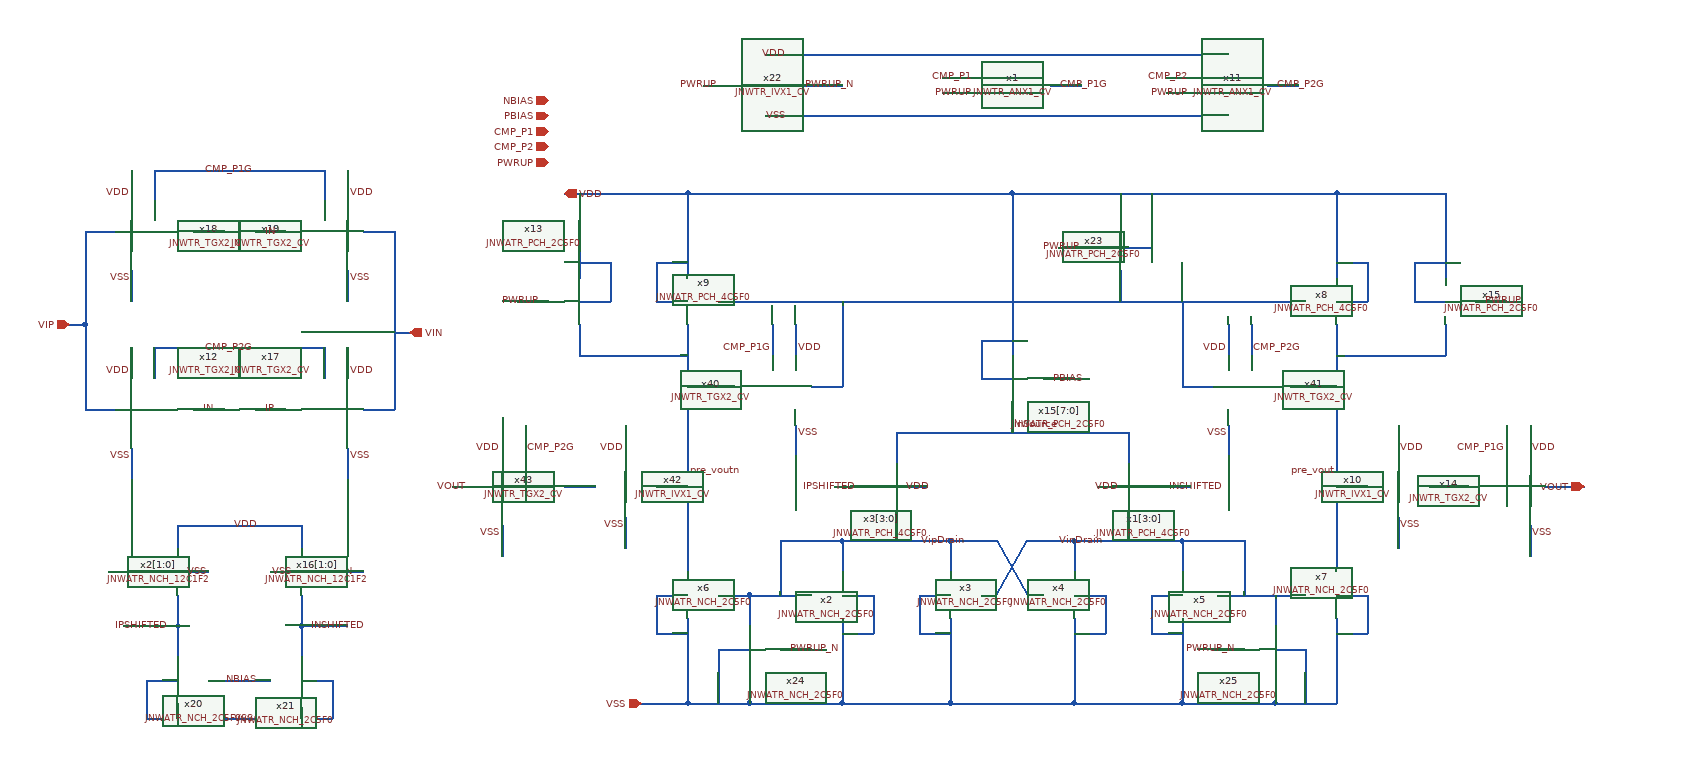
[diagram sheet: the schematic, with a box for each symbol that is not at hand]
v {xschem version=3.4.6 file_version=1.2}
G {}
K {}
V {}
S {}
E {}
N 1240 -550 1240 -510 {
lab=VipDrain}
N 1320 -550 1380 -550 {
lab=VipDrain}
N 1380 -550 1380 -510 {
lab=VipDrain}
N 1540 -550 1540 -510 {
lab=VinDrain}
N 1600 -550 1680 -550 {
lab=VinDrain}
N 1420 -480 1440 -480 {
lab=VinDrain}
N 1440 -480 1480 -550 {
lab=VinDrain}
N 1480 -480 1500 -480 {
lab=VipDrain}
N 1440 -550 1480 -480 {
lab=VipDrain}
N 1380 -550 1440 -550 {
lab=VipDrain}
N 1480 -550 1540 -550 {
lab=VinDrain}
N 1160 -550 1240 -550 {
lab=VipDrain}
N 1160 -550 1160 -480 {
lab=VipDrain}
N 1240 -860 1240 -750 {
lab=#net1}
N 1650 -1000 1880 -1000 {
lab=VDD}
N 1800 -340 1880 -340 {
lab=VSS}
N 1310 -690 1310 -650 {
lab=inSource}
N 1610 -690 1610 -650 {
lab=inSource}
N 2100 -700 2100 -660 {
lab=CMP_P1G}
N 2150 -620 2200 -620 {
lab=VOUT}
N 260 -830 260 -720 {
lab=VIP}
N 260 -950 300 -950 {
lab=VIP}
N 260 -720 300 -720 {
lab=VIP}
N 660 -950 660 -720 {
lab=VIN}
N 620 -950 660 -950 {
lab=VIN}
N 620 -720 660 -720 {
lab=VIN}
N 350 -800 350 -760 {
lab=CMP_P2G}
N 350 -800 570 -800 {
lab=CMP_P2G}
N 570 -800 570 -760 {
lab=CMP_P2G}
N 350 -1030 350 -990 {
lab=CMP_P1G}
N 350 -1030 570 -1030 {
lab=CMP_P1G}
N 570 -1030 570 -990 {
lab=CMP_P1G}
N 1230 -620 1270 -620 {lab=IPSHIFTED}
N 260 -950 260 -830 {
lab=VIP}
N 1650 -620 1690 -620 {lab=INSHIFTED}
N 1540 -550 1600 -550 {
lab=VinDrain}
N 1240 -550 1320 -550 {
lab=VipDrain}
N 1500 -760 1540 -760 {lab=PBIAS}
N 1460 -730 1460 -690 {lab=inSource}
N 290 -510 330 -510 {lab=IP}
N 1310 -690 1610 -690 {
lab=inSource}
N 380 -570 540 -570 {lab=VDD}
N 380 -570 380 -540 {lab=VDD}
N 540 -570 540 -540 {lab=VDD}
N 420 -370 500 -370 {lab=NBIAS}
N 580 -510 620 -510 {lab=IN}
N 580 -370 580 -320 {lab=VSS}
N 340 -320 580 -320 {lab=VSS}
N 340 -370 340 -320 {lab=VSS}
N 310 -440 380 -440 {lab=IPSHIFTED}
N 540 -440 600 -440 {lab=INSHIFTED}
N 540 -480 540 -440 {lab=INSHIFTED}
N 380 -480 380 -440 {lab=IPSHIFTED}
N 540 -440 540 -400 {lab=INSHIFTED}
N 380 -440 380 -400 {lab=IPSHIFTED}
N 240 -830 260 -830 {lab=VIP}
N 1060 -1140 1100 -1140 {lab=PWRUP}
N 1180 -1140 1240 -1140 {lab=PWRUP_N}
N 1600 -900 1600 -860 {lab=#net1}
N 1080 -860 1840 -860 {
lab=#net1}
N 1120 -480 1120 -440 {lab=VipDrain}
N 1080 -480 1120 -480 {
lab=VipDrain}
N 1800 -480 1800 -440 {lab=VinDrain}
N 480 -720 520 -720 {lab=IP}
N 480 -950 520 -950 {lab=IN}
N 2000 -620 2050 -620 {lab=#net2}
N 1680 -860 1680 -750 {lab=#net1}
N 1200 -750 1240 -750 {
lab=#net1}
N 1150 -830 1150 -790 {
lab=CMP_P1G}
N 1769.614593087707 -830 1769.614593087707 -790 {
lab=CMP_P2G}
N 1040 -750 1100 -750 {lab=pre_voutn}
N 1820 -750 1880 -750 {lab=pre_vout}
N 1680 -750 1720 -750 {lab=#net1}
N 880 -620 920 -620 {
lab=#net3}
N 830 -700 830 -640 {
lab=CMP_P2G}
N 735 -620 780 -620 {
lab=VOUT}
N 1000 -620 1040 -620 {lab=pre_voutn}
N 1040 -1000 1460 -1000 {
lab=VDD}
N 1460 -1000 1460 -790 {lab=VDD}
N 1040 -1000 1040 -890 {lab=VDD}
N 880 -1000 1040 -1000 {
lab=VDD}
N 1880 -620 1920 -620 {lab=pre_vout}
N 1000 -480 1000 -430 {lab=VSS}
N 980 -340 1040 -340 {
lab=VSS}
N 1040 -340 1120 -340 {
lab=VSS}
N 1080 -410 1080 -340 {lab=VSS}
N 1120 -340 1240 -340 {
lab=VSS}
N 1240 -450 1240 -340 {lab=VSS}
N 1380 -450 1380 -340 {lab=VSS}
N 1240 -340 1380 -340 {
lab=VSS}
N 1380 -340 1540 -340 {
lab=VSS}
N 1680 -450 1680 -340 {lab=VSS}
N 1540 -340 1680 -340 {
lab=VSS}
N 1680 -340 1800 -340 {
lab=VSS}
N 1840 -410 1840 -340 {lab=VSS}
N 1880 -450 1880 -340 {lab=VSS}
N 1640 -1000 1640 -930 {lab=VDD}
N 1600 -1000 1600 -960 {lab=VDD}
N 1460 -1000 1650 -1000 {
lab=VDD}
N 1790 -1140 1830 -1140 {lab=CMP_P2G}
N 1510 -1140 1550 -1140 {lab=CMP_P1G}
N 1370 -1150 1420 -1150 {lab=CMP_P1}
N 1370 -1130 1420 -1130 {lab=PWRUP}
N 1660 -1130 1700 -1130 {lab=PWRUP}
N 1660 -1150 1700 -1150 {lab=CMP_P2}
N 1140 -1180 1740 -1180 {lab=VDD}
N 1140 -1100 1740 -1100 {lab=VSS}
N 1880 -860 1920 -860 {lab=VDD}
N 1880 -1000 1880 -890 {lab=VDD}
N 1880 -910 1920 -910 {lab=VDD}
N 1880 -790 2020 -790 {lab=pre_vout}
N 1570 -930 1610 -930 {lab=VDD}
N 1605 -930 1640 -930 {lab=VDD}
N 400 -950 440 -950 {lab=IP}
N 400 -720 440 -720 {lab=IN}
N 320 -900 320 -860 {lab=VSS}
N 320 -1030 320 -990 {lab=VDD}
N 320 -670 320 -630 {lab=VSS}
N 320 -800 320 -760 {lab=VDD}
N 600 -900 600 -860 {lab=VSS}
N 600 -1030 600 -990 {lab=VDD}
N 600 -670 600 -630 {lab=VSS}
N 600 -800 600 -760 {lab=VDD}
N 660 -820 680 -820 {lab=VIN}
N 340 -370 380 -370 {lab=VSS}
N 380 -340 380 -320 {lab=VSS}
N 540 -370 580 -370 {lab=VSS}
N 540 -335 540 -320 {lab=VSS}
N 380 -510 420 -510 {lab=VSS}
N 500 -510 540 -510 {lab=VSS}
N 800 -710 800 -660 {lab=VDD}
N 800 -570 800 -530 {lab=VSS}
N 960 -700 960 -660 {lab=VDD}
N 960 -580 960 -540 {lab=VSS}
N 900 -830 900 -790 {lab=pre_voutn}
N 900 -790 1040 -790 {lab=pre_voutn}
N 900 -1000 900 -890 {lab=VDD}
N 1000 -910 1040 -910 {lab=VDD}
N 1000 -910 1000 -860 {lab=VDD}
N 1000 -860 1040 -860 {lab=VDD}
N 2020 -830 2020 -790 {lab=pre_vout}
N 2020 -1000 2020 -890 {lab=VDD}
N 1920 -910 1920 -860 {lab=VDD}
N 1180 -830 1180 -790 {lab=VDD}
N 1180 -700 1180 -660 {lab=VSS}
N 1739.614593087707 -830 1739.614593087707 -790 {lab=VDD}
N 1739.614593087707 -700 1739.614593087707 -660 {lab=VSS}
N 820 -860 860 -860 {lab=PWRUP}
N 1420 -760 1460 -760 {lab=VDD}
N 1420 -810 1420 -760 {lab=VDD}
N 1420 -810 1460 -810 {lab=VDD}
N 2130 -570 2130 -530 {lab=VSS}
N 2130 -700 2130 -660 {lab=VDD}
N 1960 -700 1960 -660 {lab=VDD}
N 1960 -580 1960 -540 {lab=VSS}
N 2060 -860 2100 -860 {lab=PWRUP}
N 1520 -930 1560 -930 {lab=PWRUP}
N 1800 -410 1840 -410 {lab=VSS}
N 1800 -380 1800 -340 {lab=VSS}
N 1080 -410 1120 -410 {lab=VSS}
N 1120 -380 1120 -340 {lab=VSS}
N 1240 -480 1280 -480 {lab=VSS}
N 1280 -480 1280 -430 {lab=VSS}
N 1240 -430 1280 -430 {lab=VSS}
N 1340 -430 1380 -430 {lab=VSS}
N 1340 -480 1340 -430 {lab=VSS}
N 1340 -480 1380 -480 {lab=VSS}
N 1540 -430 1580 -430 {lab=VSS}
N 1580 -480 1580 -430 {lab=VSS}
N 1540 -480 1580 -480 {lab=VSS}
N 1680 -550 1680 -510 {lab=VinDrain}
N 1640 -480 1680 -480 {lab=VSS}
N 1640 -480 1640 -430 {lab=VSS}
N 1640 -430 1680 -430 {lab=VSS}
N 1725 -480 1840 -480 {lab=VinDrain}
N 1120 -480 1200 -480 {lab=VipDrain}
N 1680 -550 1760 -550 {lab=VinDrain}
N 1760 -550 1760 -480 {lab=VinDrain}
N 1310 -590 1310 -550 {lab=VipDrain}
N 1610 -590 1610 -550 {lab=VinDrain}
N 1000 -480 1040 -480 {lab=VSS}
N 1040 -450 1040 -340 {lab=VSS}
N 1720 -410 1760 -410 {lab=PWRUP_N}
N 1160 -410 1200 -410 {lab=PWRUP_N}
N 1310 -620 1350 -620 {lab=VDD}
N 1570 -620 1610 -620 {lab=VDD}
N 1880 -830 1880 -510 {lab=pre_vout}
N 1040 -830 1040 -510 {lab=pre_voutn}
N 1880 -480 1920 -480 {lab=VSS}
N 1920 -480 1920 -430 {lab=VSS}
N 1880 -430 1920 -430 {lab=VSS}
N 1000 -430 1040 -430 {lab=VSS}
N 1880 -1000 2020 -1000 {lab=VDD}
N 1980 -860 2020 -860 {lab=VDD}
N 1980 -910 1980 -860 {lab=VDD}
N 1980 -910 2020 -910 {lab=VDD}
N 900 -860 940 -860 {lab=VDD}
N 940 -910 940 -860 {lab=VDD}
N 900 -910 940 -910 {lab=VDD}
N 1540 -450 1540 -340 {lab=VSS}
C {devices/ipin.sym} 980 -340 0 0 {name=p2 lab=VSS
}
C {devices/ipin.sym} 880 -1000 2 1 {name=p3 lab=VDD
}
C {devices/ipin.sym} 860 -1100 0 0 {name=p1 lab=PBIAS
}
C {devices/ipin.sym} 680 -820 0 1 {name=p5 lab=VIN
}
C {devices/ipin.sym} 240 -830 0 0 {name=p6 lab=VIP
}
C {JNW_ATR_SKY130A/JNWATR_NCH_2C5F0.sym} 1200 -480 0 0 {name=x2 }
C {JNW_ATR_SKY130A/JNWATR_NCH_2C5F0.sym} 1420 -480 0 1 {name=x3 }
C {JNW_ATR_SKY130A/JNWATR_NCH_2C5F0.sym} 1500 -480 0 0 {name=x4 }
C {JNW_ATR_SKY130A/JNWATR_NCH_2C5F0.sym} 1720 -480 0 1 {name=x5 }
C {JNW_ATR_SKY130A/JNWATR_NCH_2C5F0.sym} 1080 -480 0 1 {name=x6 }
C {JNW_ATR_SKY130A/JNWATR_NCH_2C5F0.sym} 1840 -480 0 0 {name=x7 }
C {JNW_ATR_SKY130A/JNWATR_PCH_4C5F0.sym} 1840 -860 0 0 {name=x8 }
C {JNW_ATR_SKY130A/JNWATR_PCH_4C5F0.sym} 1080 -860 0 1 {name=x9 }
C {devices/opin.sym} 2200 -620 2 1 {name=p7 lab=VOUT}
C {JNW_TR_SKY130A/JNWTR_IVX1_CV.sym} 1920 -620 0 0 {name=x10 }
C {devices/ipin.sym} 860 -1060 0 0 {name=p10 lab=CMP_P2
}
C {devices/lab_wire.sym} 1960 -570 2 0 {name=p19 sig_type=std_logic lab=VSS}
C {JNW_TR_SKY130A/JNWTR_TGX2_CV.sym} 2040 -620 0 0 {name=x14 }
C {devices/lab_wire.sym} 2130 -670 0 1 {name=p20 sig_type=std_logic lab=VDD}
C {devices/lab_wire.sym} 2130 -560 2 0 {name=p21 sig_type=std_logic lab=VSS}
C {devices/lab_wire.sym} 410 -720 0 1 {name=p32 sig_type=std_logic lab=IN}
C {devices/lab_wire.sym} 410 -950 0 1 {name=p33 sig_type=std_logic lab=IP}
C {devices/lab_wire.sym} 330 -510 0 0 {name=p34 sig_type=std_logic lab=IP}
C {devices/lab_wire.sym} 590 -510 0 1 {name=p35 sig_type=std_logic lab=IN}
C {devices/ipin.sym} 860 -1080 0 0 {name=p11 lab=CMP_P1
}
C {devices/lab_wire.sym} 1580 -550 0 0 {name=p12 sig_type=std_logic lab=VinDrain}
C {devices/lab_wire.sym} 1340 -550 0 1 {name=p13 sig_type=std_logic lab=VipDrain}
C {devices/lab_wire.sym} 1040 -640 0 1 {name=p37 sig_type=std_logic lab=pre_voutn}
C {devices/lab_wire.sym} 1880 -640 0 0 {name=p38 sig_type=std_logic lab=pre_vout}
C {JNW_TR_SKY130A/JNWTR_TGX2_CV.sym} 410 -720 0 1 {name=x12 }
C {devices/lab_wire.sym} 320 -770 0 0 {name=p29 sig_type=std_logic lab=VDD}
C {devices/lab_wire.sym} 320 -660 2 1 {name=p30 sig_type=std_logic lab=VSS}
C {JNW_TR_SKY130A/JNWTR_TGX2_CV.sym} 510 -720 0 0 {name=x17 }
C {devices/lab_wire.sym} 600 -770 0 1 {name=p31 sig_type=std_logic lab=VDD}
C {devices/lab_wire.sym} 600 -660 2 0 {name=p36 sig_type=std_logic lab=VSS}
C {JNW_TR_SKY130A/JNWTR_TGX2_CV.sym} 410 -950 0 1 {name=x18 }
C {devices/lab_wire.sym} 320 -1000 0 0 {name=p39 sig_type=std_logic lab=VDD}
C {devices/lab_wire.sym} 320 -890 2 1 {name=p40 sig_type=std_logic lab=VSS}
C {JNW_TR_SKY130A/JNWTR_TGX2_CV.sym} 510 -950 0 0 {name=x19 }
C {devices/lab_wire.sym} 600 -1000 0 1 {name=p41 sig_type=std_logic lab=VDD}
C {devices/lab_wire.sym} 600 -890 2 0 {name=p42 sig_type=std_logic lab=VSS}
C {devices/lab_wire.sym} 490 -720 0 1 {name=p43 sig_type=std_logic lab=IP}
C {devices/lab_wire.sym} 510 -950 0 0 {name=p44 sig_type=std_logic lab=IN}
C {JNW_ATR_SKY130A/JNWATR_PCH_2C5F0.sym} 1500 -760 0 1 {name=x15[7:0]}
C {devices/lab_wire.sym} 1460 -700 0 1 {name=p47 sig_type=std_logic lab=inSource}
C {devices/lab_wire.sym} 1960 -670 0 1 {name=p48 sig_type=std_logic lab=VDD}
C {devices/lab_wire.sym} 1510 -760 0 1 {name=p23 sig_type=std_logic lab=PBIAS}
C {devices/ipin.sym} 860 -1120 0 0 {name=p9 lab=NBIAS
}
C {JNW_ATR_SKY130A/JNWATR_NCH_12C1F2.sym} 340 -510 0 0 {name=x2[1:0]}
C {JNW_ATR_SKY130A/JNWATR_NCH_12C1F2.sym} 580 -510 0 1 {name=x16[1:0]}
C {devices/lab_wire.sym} 530 -510 0 0 {name=p14 sig_type=std_logic lab=VSS}
C {devices/lab_wire.sym} 390 -510 0 1 {name=p15 sig_type=std_logic lab=VSS}
C {JNW_ATR_SKY130A/JNWATR_PCH_4C5F0.sym} 1270 -620 0 0 {name=x3[3:0]}
C {devices/lab_wire.sym} 1320 -620 0 1 {name=p4 sig_type=std_logic lab=VDD}
C {devices/lab_wire.sym} 450 -570 0 1 {name=p16 sig_type=std_logic lab=VDD}
C {JNW_ATR_SKY130A/JNWATR_NCH_2C5F0.sym} 420 -370 0 1 {name=x20 }
C {JNW_ATR_SKY130A/JNWATR_NCH_2C5F0.sym} 500 -370 0 0 {name=x21 }
C {devices/lab_wire.sym} 450 -320 0 1 {name=p17 sig_type=std_logic lab=VSS}
C {devices/lab_wire.sym} 440 -370 0 1 {name=p24 sig_type=std_logic lab=NBIAS}
C {devices/lab_wire.sym} 370 -440 0 0 {name=p25 sig_type=std_logic lab=IPSHIFTED}
C {devices/lab_wire.sym} 550 -440 0 1 {name=p26 sig_type=std_logic lab=INSHIFTED}
C {devices/lab_wire.sym} 1660 -620 0 1 {name=p27 sig_type=std_logic lab=INSHIFTED}
C {devices/lab_wire.sym} 1260 -620 0 0 {name=p28 sig_type=std_logic lab=IPSHIFTED}
C {JNW_ATR_SKY130A/JNWATR_PCH_4C5F0.sym} 1650 -620 0 1 {name=x1[3:0]}
C {JNW_TR_SKY130A/JNWTR_IVX1_CV.sym} 1100 -1140 0 0 {name=x22 }
C {devices/lab_wire.sym} 1080 -1140 0 0 {name=p50 sig_type=std_logic lab=PWRUP}
C {devices/lab_wire.sym} 1190 -1140 0 1 {name=p55 sig_type=std_logic lab=PWRUP_N}
C {devices/lab_wire.sym} 1170 -1100 2 1 {name=p56 sig_type=std_logic lab=VSS}
C {devices/lab_wire.sym} 1170 -1180 0 0 {name=p57 sig_type=std_logic lab=VDD}
C {JNW_ATR_SKY130A/JNWATR_PCH_2C5F0.sym} 1560 -930 0 0 {name=x23 }
C {devices/lab_wire.sym} 1550 -930 0 0 {name=p58 sig_type=std_logic lab=PWRUP}
C {JNW_ATR_SKY130A/JNWATR_NCH_2C5F0.sym} 1160 -410 0 1 {name=x24 }
C {devices/lab_wire.sym} 1170 -410 0 1 {name=p59 sig_type=std_logic lab=PWRUP_N}
C {JNW_ATR_SKY130A/JNWATR_NCH_2C5F0.sym} 1760 -410 0 0 {name=x25 }
C {devices/lab_wire.sym} 1750 -410 0 0 {name=p60 sig_type=std_logic lab=PWRUP_N}
C {devices/ipin.sym} 860 -1040 0 0 {name=p61 lab=PWRUP
}
C {JNW_TR_SKY130A/JNWTR_TGX2_CV.sym} 1090 -750 0 0 {name=x40 }
C {devices/lab_wire.sym} 1180 -690 2 0 {name=p66 sig_type=std_logic lab=VSS}
C {JNW_TR_SKY130A/JNWTR_TGX2_CV.sym} 1829.614593087707 -750 0 1 {name=x41 }
C {devices/lab_wire.sym} 1739.614593087707 -800 0 0 {name=p88 sig_type=std_logic lab=VDD}
C {devices/lab_wire.sym} 1739.614593087707 -690 2 1 {name=p96 sig_type=std_logic lab=VSS}
C {JNW_TR_SKY130A/JNWTR_IVX1_CV.sym} 1000 -620 0 1 {name=x42 }
C {devices/lab_wire.sym} 960 -670 0 0 {name=p98 sig_type=std_logic lab=VDD}
C {devices/lab_wire.sym} 960 -570 2 1 {name=p99 sig_type=std_logic lab=VSS}
C {JNW_TR_SKY130A/JNWTR_TGX2_CV.sym} 890 -620 0 1 {name=x43 }
C {devices/lab_wire.sym} 800 -670 0 0 {name=p100 sig_type=std_logic lab=VDD}
C {devices/lab_wire.sym} 800 -560 2 1 {name=p101 sig_type=std_logic lab=VSS}
C {devices/lab_wire.sym} 755 -620 0 0 {name=p103 sig_type=std_logic lab=VOUT}
C {JNW_TR_SKY130A/JNWTR_ANX1_CV.sym} 1420 -1130 0 0 {name=x1 }
C {JNW_TR_SKY130A/JNWTR_ANX1_CV.sym} 1700 -1130 0 0 {name=x11 }
C {devices/lab_wire.sym} 1410 -1130 0 0 {name=p18 sig_type=std_logic lab=PWRUP}
C {devices/lab_wire.sym} 1690 -1130 0 0 {name=p49 sig_type=std_logic lab=PWRUP}
C {devices/lab_wire.sym} 1410 -1150 0 0 {name=p51 sig_type=std_logic lab=CMP_P1}
C {devices/lab_wire.sym} 1690 -1150 0 0 {name=p52 sig_type=std_logic lab=CMP_P2}
C {devices/lab_wire.sym} 1800 -1140 0 1 {name=p53 sig_type=std_logic lab=CMP_P2G}
C {devices/lab_wire.sym} 1520 -1140 0 1 {name=p54 sig_type=std_logic lab=CMP_P1G}
C {devices/lab_wire.sym} 830 -670 0 1 {name=p46 sig_type=std_logic lab=CMP_P2G}
C {devices/lab_wire.sym} 1769.614593087707 -800 0 1 {name=p62 sig_type=std_logic lab=CMP_P2G}
C {devices/lab_wire.sym} 1150 -800 0 0 {name=p64 sig_type=std_logic lab=CMP_P1G}
C {devices/lab_wire.sym} 2100 -670 0 0 {name=p22 sig_type=std_logic lab=CMP_P1G}
C {JNW_ATR_SKY130A/JNWATR_PCH_2C5F0.sym} 860 -860 0 0 {name=x13 }
C {JNW_ATR_SKY130A/JNWATR_PCH_2C5F0.sym} 2060 -860 0 1 {name=x15 }
C {devices/lab_wire.sym} 850 -860 0 0 {name=p67 sig_type=std_logic lab=PWRUP}
C {devices/lab_wire.sym} 2070 -860 0 1 {name=p68 sig_type=std_logic lab=PWRUP}
C {devices/lab_wire.sym} 480 -800 0 0 {name=p69 sig_type=std_logic lab=CMP_P2G}
C {devices/lab_wire.sym} 480 -1030 0 0 {name=p70 sig_type=std_logic lab=CMP_P1G}
C {devices/lab_wire.sym} 1180 -800 0 1 {name=p45 sig_type=std_logic lab=VDD}
C {devices/lab_wire.sym} 1600 -620 0 0 {name=p8 sig_type=std_logic lab=VDD}
